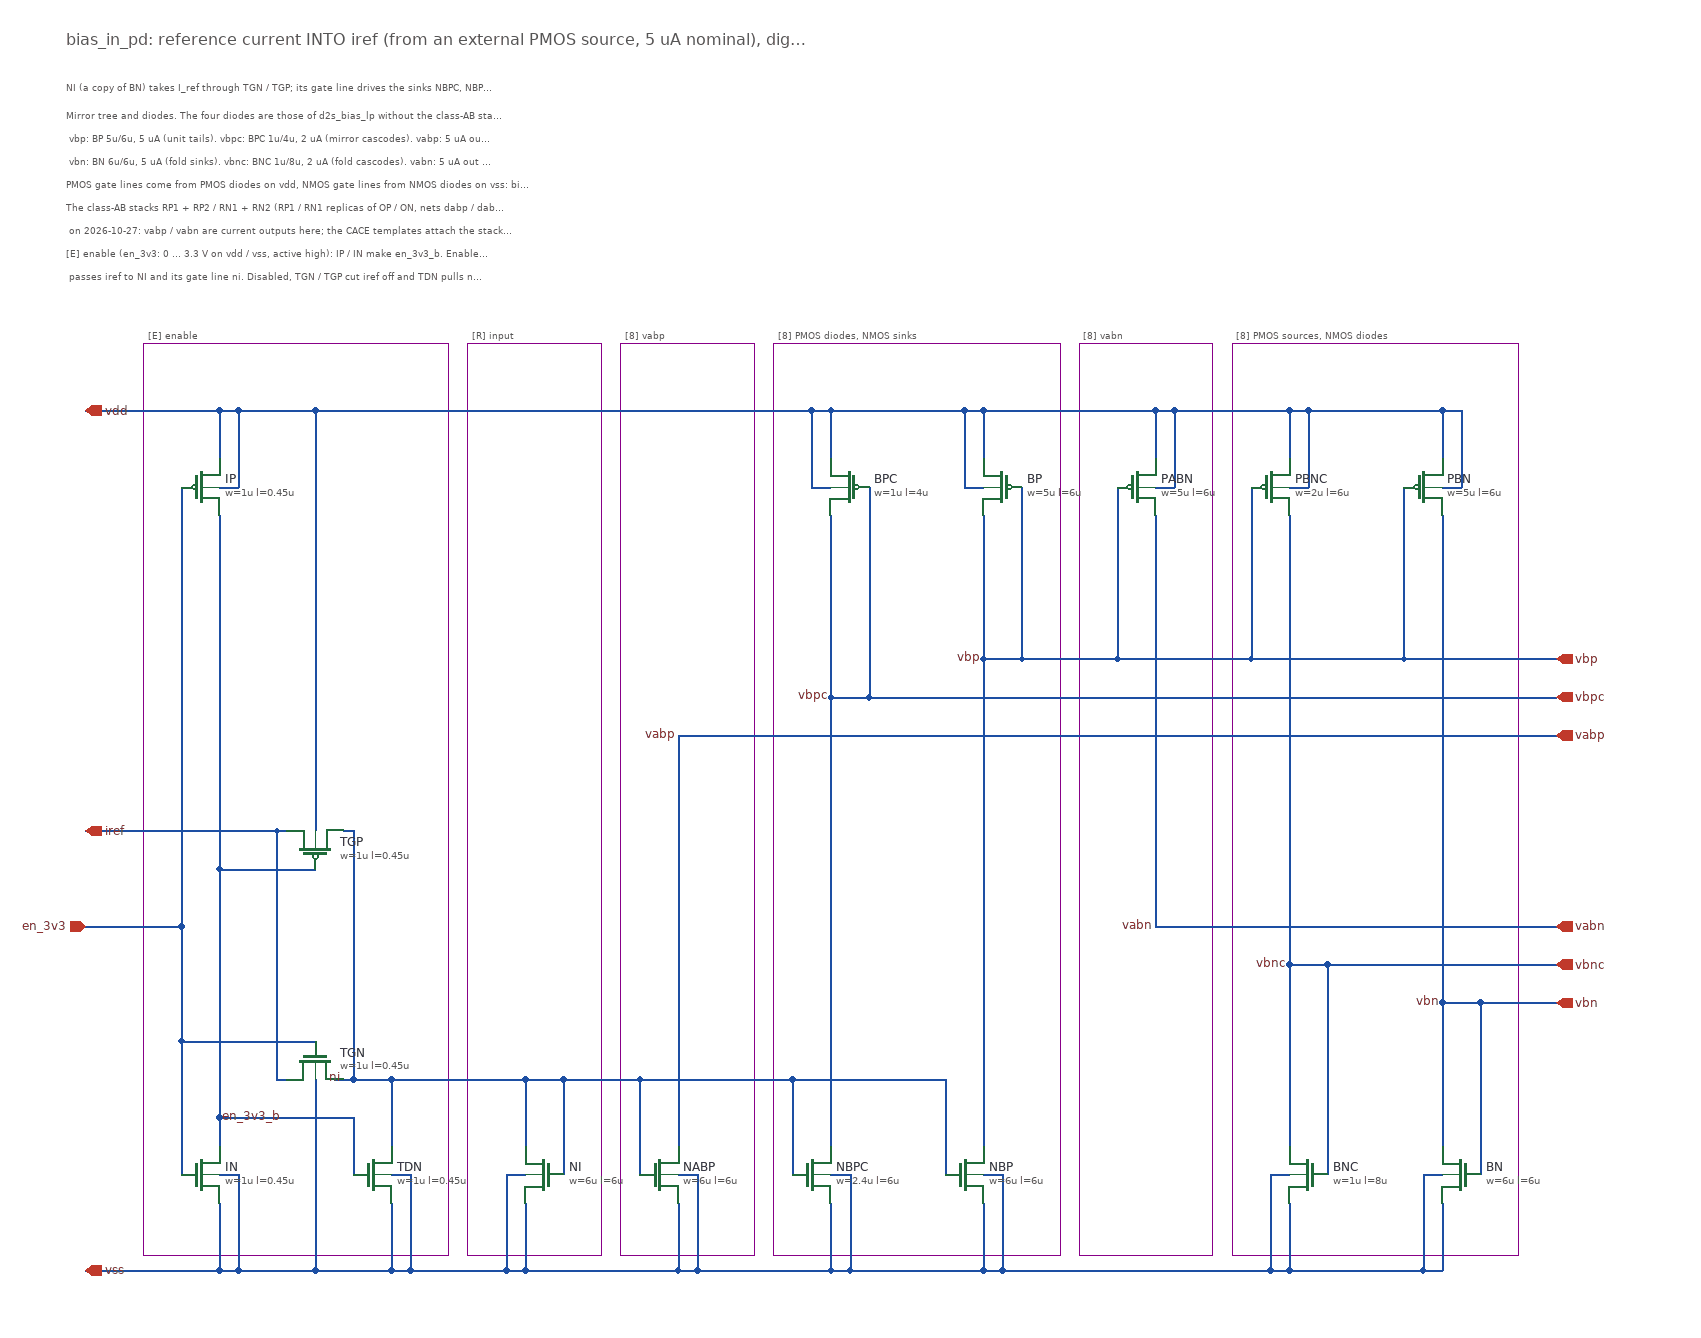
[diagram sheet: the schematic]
v {xschem version=3.4.8RC file_version=1.3}
G {}
K {}
V {}
S {}
F {}
E {}
P 10 5 500 -1110 640 -1110 640 -155 500 -155 500 -1110 {dash=6}
P 10 5 820 -1110 1120 -1110 1120 -155 820 -155 820 -1110 {dash=6}
P 10 5 660 -1110 800 -1110 800 -155 660 -155 660 -1110 {dash=6}
P 10 5 1300 -1110 1600 -1110 1600 -155 1300 -155 1300 -1110 {dash=6}
P 10 5 1140 -1110 1280 -1110 1280 -155 1140 -155 1140 -1110 {dash=6}
P 10 5 160 -1110 480 -1110 480 -155 160 -155 160 -1110 {dash=6}
T {[R] input} 505 -1130 0 0 0.3 0.3 {layer=10}
T {bias_in_pd: reference current INTO iref (from an external PMOS source, 5 uA nominal), digital enable en_3v3} 80 -1440 0 0 0.5 0.5 {}
T {NI (a copy of BN) takes I_ref through TGN / TGP; its gate line drives the sinks NBPC, NBP, NABP out of the PMOS diodes; BP's gate line drives the sources PBNC, PBN, PABN into the NMOS diodes.} 80 -1390 0 0 0.3 0.3 {}
T {Mirror tree and diodes. The four diodes are those of d2s_bias_lp without the class-AB stacks and set the bias voltages:} 80 -1360 0 0 0.3 0.3 {layer=10}
T {   vbp: BP 5u/6u, 5 uA (unit tails).  vbpc: BPC 1u/4u, 2 uA (mirror cascodes).  vabp: 5 uA out to RP2 on RP1 (ABP, FPL).} 80 -1336 0 0 0.3 0.3 {layer=10}
T {   vbn: BN 6u/6u, 5 uA (fold sinks).  vbnc: BNC 1u/8u, 2 uA (fold cascodes).  vabn: 5 uA out to RN2 on RN1 (ABN, FNL).} 80 -1312 0 0 0.3 0.3 {layer=10}
T {PMOS gate lines come from PMOS diodes on vdd, NMOS gate lines from NMOS diodes on vss: bias crosses blocks as currents.} 80 -1288 0 0 0.3 0.3 {layer=10}
T {The class-AB stacks RP1 + RP2 / RN1 + RN2 (RP1 / RN1 replicas of OP / ON, nets dabp / dabn) moved to the pad (RP2 / RN2 in d2s_mpdda_pd, RP1 / RN1 in d2s_out_p / d2s_out_n since 2026-10-28)} 80 -1264 0 0 0.3 0.3 {layer=10}
T {   on 2026-10-27: vabp / vabn are current outputs here; the CACE templates attach the stacks as fixtures.} 80 -1240 0 0 0.3 0.3 {layer=10}
T {[8] PMOS diodes, NMOS sinks} 825 -1130 0 0 0.3 0.3 {layer=10}
T {[8] vabp} 665 -1130 0 0 0.3 0.3 {layer=10}
T {[8] PMOS sources, NMOS diodes} 1305 -1130 0 0 0.3 0.3 {layer=10}
T {[8] vabn} 1145 -1130 0 0 0.3 0.3 {layer=10}
T {[E] enable} 165 -1130 0 0 0.3 0.3 {layer=10}
T {[E] enable (en_3v3: 0 ... 3.3 V on vdd / vss, active high): IP / IN make en_3v3_b. Enabled, the transmission gate TGN / TGP} 80 -1216 0 0 0.3 0.3 {layer=10}
T {   passes iref to NI and its gate line ni. Disabled, TGN / TGP cut iref off and TDN pulls ni to vss: NI and the tree are off.} 80 -1192 0 0 0.3 0.3 {layer=10}
N 420 -340 560 -340 {lab=ni}
N 440 -140 540 -140 {lab=vss}
N 540 -240 540 -140 {lab=vss}
N 540 -240 560 -240 {lab=vss}
N 540 -140 560 -140 {lab=vss}
N 560 -340 600 -340 {lab=ni}
N 560 -210 560 -140 {lab=vss}
N 560 -140 720 -140 {lab=vss}
N 600 -340 680 -340 {lab=ni}
N 680 -1040 860 -1040 {lab=vdd}
N 680 -340 840 -340 {lab=ni}
N 720 -700 720 -270 {lab=vabp}
N 720 -700 760 -700 {lab=vabp}
N 720 -240 740 -240 {lab=vss}
N 720 -210 720 -140 {lab=vss}
N 720 -140 740 -140 {lab=vss}
N 740 -240 740 -140 {lab=vss}
N 740 -140 880 -140 {lab=vss}
N 760 -700 1640 -700 {lab=vabp}
N 840 -340 1000 -340 {lab=ni}
N 860 -1040 860 -960 {lab=vdd}
N 860 -1040 880 -1040 {lab=vdd}
N 860 -960 880 -960 {lab=vdd}
N 880 -1040 880 -990 {lab=vdd}
N 880 -1040 1020 -1040 {lab=vdd}
N 880 -930 880 -740 {lab=vbpc}
N 880 -740 880 -270 {lab=vbpc}
N 880 -740 920 -740 {lab=vbpc}
N 880 -240 900 -240 {lab=vss}
N 880 -210 880 -140 {lab=vss}
N 880 -140 900 -140 {lab=vss}
N 900 -240 900 -140 {lab=vss}
N 900 -140 1040 -140 {lab=vss}
N 920 -960 920 -740 {lab=vbpc}
N 920 -740 1640 -740 {lab=vbpc}
N 1020 -1040 1020 -960 {lab=vdd}
N 1020 -1040 1040 -1040 {lab=vdd}
N 1020 -960 1040 -960 {lab=vdd}
N 1040 -1040 1040 -990 {lab=vdd}
N 1040 -1040 1220 -1040 {lab=vdd}
N 1040 -930 1040 -780 {lab=vbp}
N 1040 -780 1040 -270 {lab=vbp}
N 1040 -780 1080 -780 {lab=vbp}
N 1040 -240 1060 -240 {lab=vss}
N 1040 -210 1040 -140 {lab=vss}
N 1040 -140 1060 -140 {lab=vss}
N 1060 -240 1060 -140 {lab=vss}
N 1060 -140 1180 -140 {lab=vss}
N 1080 -960 1080 -780 {lab=vbp}
N 1080 -780 1180 -780 {lab=vbp}
N 1180 -960 1180 -780 {lab=vbp}
N 1180 -780 1320 -780 {lab=vbp}
N 1180 -140 1340 -140 {lab=vss}
N 1220 -1040 1220 -990 {lab=vdd}
N 1220 -1040 1240 -1040 {lab=vdd}
N 1220 -960 1240 -960 {lab=vdd}
N 1220 -930 1220 -500 {lab=vabn}
N 1220 -500 1260 -500 {lab=vabn}
N 1240 -1040 1240 -960 {lab=vdd}
N 1240 -1040 1360 -1040 {lab=vdd}
N 1260 -500 1640 -500 {lab=vabn}
N 1320 -960 1320 -780 {lab=vbp}
N 1320 -780 1480 -780 {lab=vbp}
N 1340 -240 1340 -140 {lab=vss}
N 1340 -240 1360 -240 {lab=vss}
N 1340 -140 1360 -140 {lab=vss}
N 1360 -1040 1360 -990 {lab=vdd}
N 1360 -1040 1380 -1040 {lab=vdd}
N 1360 -960 1380 -960 {lab=vdd}
N 1360 -930 1360 -460 {lab=vbnc}
N 1360 -460 1360 -270 {lab=vbnc}
N 1360 -460 1400 -460 {lab=vbnc}
N 1360 -210 1360 -140 {lab=vss}
N 1360 -140 1500 -140 {lab=vss}
N 1380 -1040 1380 -960 {lab=vdd}
N 1380 -1040 1520 -1040 {lab=vdd}
N 1400 -460 1400 -240 {lab=vbnc}
N 1400 -460 1640 -460 {lab=vbnc}
N 1480 -960 1480 -780 {lab=vbp}
N 1480 -780 1640 -780 {lab=vbp}
N 1500 -240 1500 -140 {lab=vss}
N 1500 -240 1520 -240 {lab=vss}
N 1500 -140 1520 -140 {lab=vss}
N 1520 -1040 1520 -990 {lab=vdd}
N 1520 -1040 1540 -1040 {lab=vdd}
N 1520 -960 1540 -960 {lab=vdd}
N 1520 -930 1520 -420 {lab=vbn}
N 1520 -420 1520 -270 {lab=vbn}
N 1520 -420 1560 -420 {lab=vbn}
N 1520 -210 1520 -140 {lab=vss}
N 1540 -1040 1540 -960 {lab=vdd}
N 1560 -420 1560 -240 {lab=vbn}
N 1560 -420 1640 -420 {lab=vbn}
N 340 -1040 680 -1040 {lab=vdd}
N 340 -140 420 -140 {lab=vss}
N 100 -500 200 -500 {lab=en_3v3}
N 200 -380 340 -380 {lab=en_3v3}
N 240 -960 260 -960 {lab=vdd}
N 240 -240 260 -240 {lab=vss}
N 240 -300 240 -270 {lab=en_3v3_b}
N 300 -600 300 -340 {lab=iref}
N 420 -240 440 -240 {lab=vss}
N 420 -140 440 -140 {lab=vss}
N 200 -380 200 -240 {lab=en_3v3}
N 240 -210 240 -140 {lab=vss}
N 260 -240 260 -140 {lab=vss}
N 240 -140 260 -140 {lab=vss}
N 380 -300 380 -240 {lab=#net1}
N 240 -300 380 -300 {lab=en_3v3_b}
N 440 -240 440 -140 {lab=vss}
N 420 -210 420 -140 {lab=vss}
N 420 -340 420 -270 {lab=ni}
N 560 -340 560 -270 {lab=ni}
N 600 -340 600 -240 {lab=ni}
N 680 -340 680 -240 {lab=ni}
N 840 -340 840 -240 {lab=ni}
N 1000 -340 1000 -240 {lab=ni}
N 200 -500 200 -380 {lab=en_3v3}
N 340 -340 340 -140 {lab=vss}
N 370 -600 380 -600 {lab=ni}
N 300 -600 310 -600 {lab=iref}
N 300 -340 310 -340 {lab=iref}
N 340 -1040 340 -600 {lab=vdd}
N 380 -600 380 -340 {lab=ni}
N 240 -560 340 -560 {lab=en_3v3_b}
N 380 -340 420 -340 {lab=ni}
N 260 -1040 340 -1040 {lab=vdd}
N 260 -140 340 -140 {lab=vss}
N 360 -340 380 -340 {lab=ni}
N 240 -1040 260 -1040 {lab=vdd}
N 100 -140 240 -140 {lab=vss}
N 100 -600 300 -600 {lab=iref}
N 240 -930 240 -560 {lab=en_3v3_b}
N 200 -960 200 -500 {lab=en_3v3}
N 260 -1040 260 -960 {lab=vdd}
N 240 -1040 240 -990 {lab=vdd}
N 100 -1040 240 -1040 {lab=vdd}
N 240 -560 240 -300 {lab=en_3v3_b}
C {sg13cmos5l_pr/sg13_hv_nmos.sym} 580 -240 0 1 {name=NI
l=6u
w=6u
ng=1
m=1
mm_ok=1
model=sg13_hv_nmos
spiceprefix=X}
C {devices/title.sym} 160 -40 0 0 {name=l0 author="Christoph Maier"}
C {sg13cmos5l_pr/sg13_hv_pmos.sym} 900 -960 0 1 {name=BPC
l=4u
w=1u
ng=1
m=1
mm_ok=1
model=sg13_hv_pmos
spiceprefix=X}
C {sg13cmos5l_pr/sg13_hv_nmos.sym} 860 -240 0 0 {name=NBPC
l=6u
w=2.4u
ng=1
m=1
mm_ok=1
model=sg13_hv_nmos
spiceprefix=X}
C {devices/lab_wire.sym} 880 -740 0 0 {name=l1 sig_type=std_logic lab=vbpc}
C {sg13cmos5l_pr/sg13_hv_pmos.sym} 1060 -960 0 1 {name=BP
l=6u
w=5u
ng=1
m=1
mm_ok=1
model=sg13_hv_pmos
spiceprefix=X}
C {sg13cmos5l_pr/sg13_hv_nmos.sym} 1020 -240 0 0 {name=NBP
l=6u
w=6u
ng=1
m=1
mm_ok=1
model=sg13_hv_nmos
spiceprefix=X}
C {devices/lab_wire.sym} 1040 -780 0 0 {name=l2 sig_type=std_logic lab=vbp}
C {sg13cmos5l_pr/sg13_hv_nmos.sym} 700 -240 0 0 {name=NABP
l=6u
w=6u
ng=1
m=1
mm_ok=1
model=sg13_hv_nmos
spiceprefix=X}
C {devices/lab_wire.sym} 720 -700 0 0 {name=l4 sig_type=std_logic lab=vabp}
C {sg13cmos5l_pr/sg13_hv_pmos.sym} 1340 -960 0 0 {name=PBNC
l=6u
w=2u
ng=1
m=1
mm_ok=1
model=sg13_hv_pmos
spiceprefix=X}
C {sg13cmos5l_pr/sg13_hv_nmos.sym} 1380 -240 0 1 {name=BNC
l=8u
w=1u
ng=1
m=1
mm_ok=1
model=sg13_hv_nmos
spiceprefix=X}
C {devices/lab_wire.sym} 1360 -460 0 0 {name=l5 sig_type=std_logic lab=vbnc}
C {sg13cmos5l_pr/sg13_hv_pmos.sym} 1500 -960 0 0 {name=PBN
l=6u
w=5u
ng=1
m=1
mm_ok=1
model=sg13_hv_pmos
spiceprefix=X}
C {sg13cmos5l_pr/sg13_hv_nmos.sym} 1540 -240 0 1 {name=BN
l=6u
w=6u
ng=1
m=1
mm_ok=1
model=sg13_hv_nmos
spiceprefix=X}
C {devices/lab_wire.sym} 1520 -420 0 0 {name=l6 sig_type=std_logic lab=vbn}
C {sg13cmos5l_pr/sg13_hv_pmos.sym} 1200 -960 0 0 {name=PABN
l=6u
w=5u
ng=1
m=1
mm_ok=1
model=sg13_hv_pmos
spiceprefix=X}
C {devices/lab_wire.sym} 1220 -500 0 0 {name=l8 sig_type=std_logic lab=vabn}
C {devices/iopin.sym} 100 -1040 0 1 {name=p1 lab=vdd}
C {devices/iopin.sym} 100 -140 0 1 {name=p2 lab=vss}
C {devices/iopin.sym} 100 -600 0 1 {name=p5 lab=iref}
C {devices/opin.sym} 1640 -780 0 0 {name=p6 lab=vbp}
C {devices/opin.sym} 1640 -420 0 0 {name=p7 lab=vbn}
C {devices/opin.sym} 1640 -740 0 0 {name=p8 lab=vbpc}
C {devices/opin.sym} 1640 -460 0 0 {name=p9 lab=vbnc}
C {devices/opin.sym} 1640 -700 0 0 {name=p10 lab=vabp}
C {devices/opin.sym} 1640 -500 0 0 {name=p11 lab=vabn}
C {devices/ipin.sym} 100 -500 0 0 {name=p12 lab=en_3v3}
C {sg13cmos5l_pr/sg13_hv_pmos.sym} 220 -960 0 0 {name=IP
l=0.45u
w=1u
ng=1
m=1
mm_ok=1
model=sg13_hv_pmos
spiceprefix=X}
C {sg13cmos5l_pr/sg13_hv_nmos.sym} 220 -240 0 0 {name=IN
l=0.45u
w=1u
ng=1
m=1
mm_ok=1
model=sg13_hv_nmos
spiceprefix=X}
C {sg13cmos5l_pr/sg13_hv_pmos.sym} 340 -580 1 1 {name=TGP
l=0.45u
w=1u
ng=1
m=1
mm_ok=1
model=sg13_hv_pmos
spiceprefix=X}
C {sg13cmos5l_pr/sg13_hv_nmos.sym} 340 -360 3 1 {name=TGN
l=0.45u
w=1u
ng=1
m=1
mm_ok=1
model=sg13_hv_nmos
spiceprefix=X}
C {sg13cmos5l_pr/sg13_hv_nmos.sym} 400 -240 0 0 {name=TDN
l=0.45u
w=1u
ng=1
m=1
mm_ok=1
model=sg13_hv_nmos
spiceprefix=X}
C {devices/lab_wire.sym} 370 -340 0 0 {name=l9 sig_type=std_logic lab=ni}
C {devices/lab_wire.sym} 240 -300 0 1 {name=l10 sig_type=std_logic lab=en_3v3_b}
